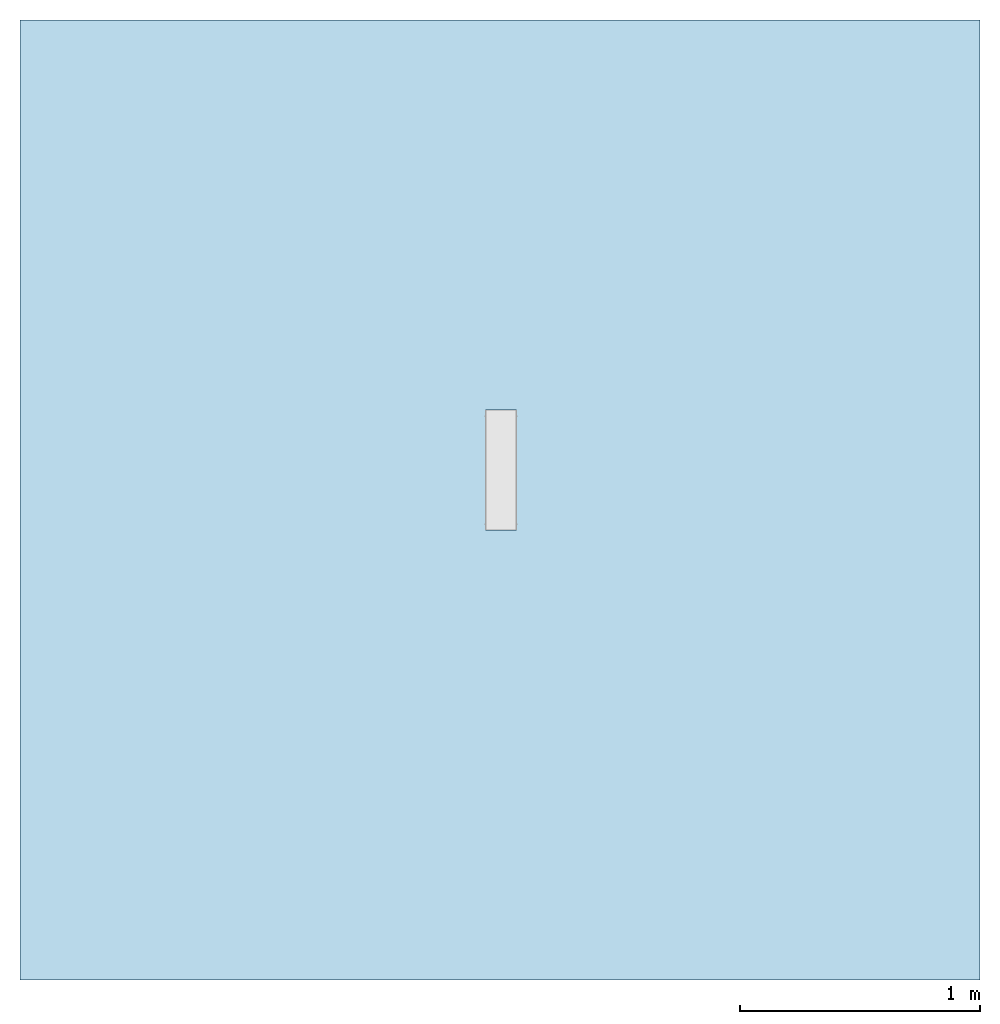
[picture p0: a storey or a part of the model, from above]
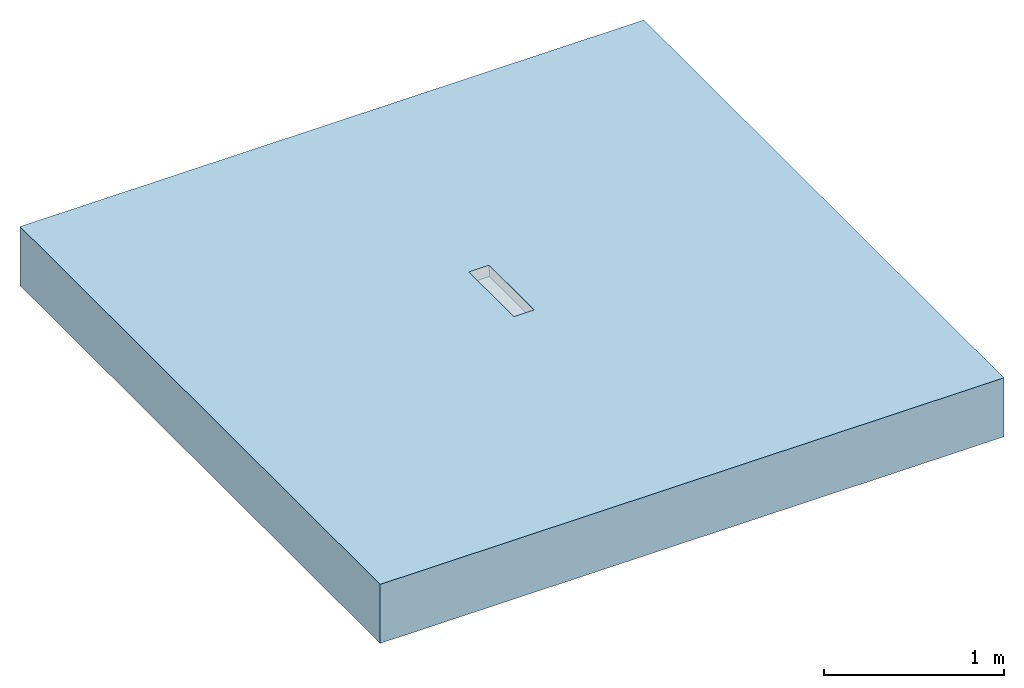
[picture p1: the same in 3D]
Properties of the parts of a building model (IFC2X3)

# File
Description: ViewDefinition [CoordinationView]
File name: Project Number
Time: 2014-06-06T14:32:18
Written by: The EXPRESS Data Manager Version 5.01.0100.02.64mod : 6 Jun 2012
Made in: 20130308_1515(x64) - Exporter 2014.0.2013.0308 - Default UI
Comment: STEP Physical File produced by: The EXPRESS Data Manager Version 5.01.0100.02.64mod : 6 Jun 2012 * Module: EDMstepFileFactory/EDMstandAlone * Creation date: Fri Jun 06 14:32:18 2014 * Host: IN-BLR-PC-0010 * Database: C:\Users\palleri\AppData\Local\Temp\{312677B8-D1D5-427A-BF4E-58D0E44710A7}\ifc * Database version: 5507 * Database creation date: Fri Jun 06 14:32:18 2014 * Schema: IFC2X3 * Model: DataRepository.ifc * Model creation date: Fri Jun 06 14:32:18 2014 * Header model: DataRepository.ifc_HeaderModel * Header model creation date: Fri Jun 06 14:32:18 2014 * EDMuser: sdai-user * EDMgroup: sdai-group * License ID and type: 5605 : Permanent license. Expiry date: * EDMstepFileFactory options: 020000

# IfcProject, Project Number
LongName: Project Name; Phase: Project Status

# IfcSite, Default
RefLatitude: 42, 21, 30, 344238; RefLongitude: -71, -3, -35, -194702; RefElevation: 0 mm

# IfcBuilding
Pset_BuildingCommon - NumberOfStoreys: 1
Other - Project Name: Project Name; Project Status: Project Status; Project Address: ## Street City, State Zip; Project Issue Date: Issue Date; Project Number: Project Number; Client Name: Owner

# IfcBuildingStorey, Level 1
LongName: Level 1; Elevation: 0 mm
Graphics - Symbol: M_Level Head - Circle: M_Level Head - Circle; Symbol at End 1 Default: no; Symbol at End 2 Default: yes; Line Pattern: Center; Line Weight: 1; Color: 0
Constraints - Elevation Base: Project Base Point; Elevation: 0 mm
Identity Data - Name: Level 1; Structural: no; Building Story: yes
Dimensions - Computation Height: 0 mm

# IfcFlowTerminal: 36940 - Adjustable Channel - Shallow Section - 500mm LG - Invert Depth 55/77mm, ACO Freedeck Adjustable Height Channel Shallow Section Galvanized Steel:36940 - Adjustable Channel - Shallow Section - 500mm LG - Invert Depth 55/77mm:309629
In: Level 1
Material: Galvanized Steel
Other - Top Piece Void Height @ Invert 2: 31 mm; Height @ Invert 2 Min & Max: 77 mm; Top Piece Void Height @ Invert 1: 31 mm; Height @ Invert 1 Min & Max: 77 mm; Nos: 16
Identity Data - Mark: 28; Watermark2: This file is water marked and users are prohibited to reproduce, adapt, distribute this information; E-mail Technical: abdtechnical@aco.co.uk; Watermark1: This file is the property of ACO Technologies PLC; Address: ACO Business Centre, Caxton Road, Bedford, MK41 0LF; Website: www.acobd.com; Fax: +44 (0)1462 851490; Manufacturer: ACO Building Drainage; Watermarked By: www.acobd.com; E-mail Sales: abdcommercial@aco.co.uk; Watermarked With: BIM Manager Premium Suite; Telephone: +44 (0)1462 816666
Dimensions - Height @ Invert 1 (55 -77mm): 77 mm; Height @ Invert 2 (55 -77mm): 77 mm; Channel End Length: -500 mm; Grating End Length: 500 mm
Phasing - Phase Created: New Construction
Constraints - Level: Level: Level 1; Moves With Nearby Elements: no
Construction - 00276 - Grating - Slotted Grating - Galvanised Steel - 1000mm long: no; 36953 - Grating - Plain Mesh - Galvanised Steel - 1000mm long: yes; End Plate Invert 2: no; 00277 - Grating - Slotted Grating - Galvanised Steel - 500mm long: no; 36952 - Grating - Plain Mesh - Galvanised Steel - 500mm long: no; End Plate Invert 1: no
Pset_ManufacturerTypeInformation - Manufacturer: ACO Building Drainage
General - NBS Specification: NBS Section R10 Gravity Rainwater Drainage Systems, Subsection 365; Channel Recyclable: Fully recyclable; Dimensions (LxWxH): 500 x 130 x 55/77; Weight (Kg): 3.1kg; Product Type: Linear Deck Drainage System; Price: POA - contact ACO; Channel Recycled Material Content: 25 - 30 %; Channel Colour: Galvanised; Channel Material: Hot Dipped Galvanised Steel; Product Range: ACO Freedeck; Maintenance Guidelines: X:\Electronic Literature\ABD Electronic Literature\Roof and Balcony Drainage\ACO Freedeck Brochure.pdf; Product Standard: BS EN 1433:2002, CE marked; Product Code: 36940; Installation Guidelines: X:\Electronic Literature\ABD Electronic Literature\Roof and Balcony Drainage\ACO Freedeck Brochure.pdf; Product Description: ACO Freedeck Adjustable Channel - Shallow Section; Load Class: A15
Model Properties - Grating Product Code 36952: Load Class A15 - Mesh Grating - 14mm x 30mm Mesh - Galvanized Steel - 500mm long - 1.6kg; Grating Product Code 00276: Load Class A15 - Slotted Grating - 10 x 80mm Slot - Galvanized Steel - 1000mm long - 2.2kg; Grating Product Code 00277: Load Class A15 - Slotted Grating - 10 x 80mm Slot - Galvanized Steel - 500mm long - 1.0kg; End Plate Product Code 36950: End Plate - Galvanized Steel for Invert Depth - 55/77mm - 0.1Kg; Grating Product Code 36953: Load Class A15 - Mesh Grating - 14mm x 30mm Mesh - Galvanized Steel - 1000mm long - 3.0kg
Materials and Finishes - Material: Galvanized Steel

# IfcOpeningElement: Recess
In: Level 1
Structural - Enable Analytical Model: no; Structural: no
Phasing - Phase Created: New Construction
Constraints - Related to Mass: no; Height Offset From Level: 0 mm; Level: Level: Level 1; Room Bounding: yes
Dimensions - Perimeter: 16000 mm; Volume: 6.3949 m3; Thickness: 400 mm; Area: 16 m2
Graphics - Coarse Scale Fill Color: 0
Materials and Finishes - Structural Material: Concrete, Broom Finish
Analytical Properties - Roughness: 1; Absorptance: 0.1; Heat Transfer Coefficient (U): 2.615; Thermal Resistance (R): 0.382409; Thermal mass: 604440
Construction - Function: Interior; Default Thickness: 400 mm

# IfcSlab: Floor:Generic Floor - 400mm, Floor:Generic Floor - 400mm:193825
In: Level 1
PredefinedType: FLOOR; Material: Concrete, Broom Finish 400 mm
Structural - Enable Analytical Model: no; Structural: no
Phasing - Phase Created: New Construction
Constraints - Related to Mass: no; Height Offset From Level: 0 mm; Level: Level: Level 1; Room Bounding: yes
Dimensions - Perimeter: 16000 mm; Volume: 6.3949 m3; Thickness: 400 mm; Area: 16 m2
Pset_SlabCommon - Reference: Generic Floor - 400mm; IsExternal: no; LoadBearing: yes; ThermalTransmittance: 2.615 kg/K/s3
Graphics - Coarse Scale Fill Color: 0
Materials and Finishes - Structural Material: Concrete, Broom Finish
Analytical Properties - Roughness: 1; Absorptance: 0.1; Heat Transfer Coefficient (U): 2.615; Thermal Resistance (R): 0.382409; Thermal mass: 604440
Construction - Function: Interior; Default Thickness: 400 mm
